VERSION 5.7 ;
  NOWIREEXTENSIONATPIN ON ;
  DIVIDERCHAR "/" ;
  BUSBITCHARS "[]" ;
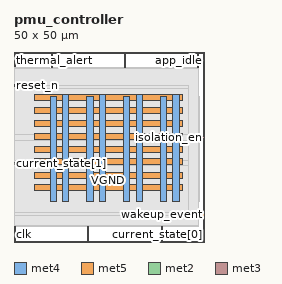
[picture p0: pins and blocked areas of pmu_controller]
MACRO pmu_controller
  CLASS BLOCK ;
  FOREIGN pmu_controller ;
  ORIGIN 0.000 0.000 ;
  SIZE 50.000 BY 50.000 ;
  PIN VGND
    DIRECTION INOUT ;
    USE GROUND ;
    PORT
      LAYER met4 ;
        RECT 12.850 10.640 14.450 38.760 ;
    END
    PORT
      LAYER met4 ;
        RECT 22.510 10.640 24.110 38.760 ;
    END
    PORT
      LAYER met4 ;
        RECT 32.170 10.640 33.770 38.760 ;
    END
    PORT
      LAYER met4 ;
        RECT 41.830 10.640 43.430 38.760 ;
    END
    PORT
      LAYER met5 ;
        RECT 5.280 16.775 44.400 18.375 ;
    END
    PORT
      LAYER met5 ;
        RECT 5.280 23.570 44.400 25.170 ;
    END
    PORT
      LAYER met5 ;
        RECT 5.280 30.365 44.400 31.965 ;
    END
    PORT
      LAYER met5 ;
        RECT 5.280 37.160 44.400 38.760 ;
    END
  END VGND
  PIN VPWR
    DIRECTION INOUT ;
    USE POWER ;
    PORT
      LAYER met4 ;
        RECT 9.550 10.640 11.150 38.320 ;
    END
    PORT
      LAYER met4 ;
        RECT 19.210 10.640 20.810 38.320 ;
    END
    PORT
      LAYER met4 ;
        RECT 28.870 10.640 30.470 38.320 ;
    END
    PORT
      LAYER met4 ;
        RECT 38.530 10.640 40.130 38.320 ;
    END
    PORT
      LAYER met5 ;
        RECT 5.280 13.475 44.400 15.075 ;
    END
    PORT
      LAYER met5 ;
        RECT 5.280 20.270 44.400 21.870 ;
    END
    PORT
      LAYER met5 ;
        RECT 5.280 27.065 44.400 28.665 ;
    END
    PORT
      LAYER met5 ;
        RECT 5.280 33.860 44.400 35.460 ;
    END
  END VPWR
  PIN app_idle
    DIRECTION INPUT ;
    USE SIGNAL ;
    ANTENNAGATEAREA 0.196500 ;
    PORT
      LAYER met2 ;
        RECT 48.390 46.000 48.670 50.000 ;
    END
  END app_idle
  PIN clk
    DIRECTION INPUT ;
    USE SIGNAL ;
    ANTENNAGATEAREA 0.852000 ;
    PORT
      LAYER met2 ;
        RECT 0.090 0.000 0.370 4.000 ;
    END
  END clk
  PIN clk_gate_en
    DIRECTION OUTPUT TRISTATE ;
    USE SIGNAL ;
    ANTENNADIFFAREA 0.795200 ;
    PORT
      LAYER met2 ;
        RECT 29.070 46.000 29.350 50.000 ;
    END
  END clk_gate_en
  PIN current_state[0]
    DIRECTION OUTPUT TRISTATE ;
    USE SIGNAL ;
    ANTENNADIFFAREA 0.795200 ;
    PORT
      LAYER met2 ;
        RECT 38.730 0.000 39.010 4.000 ;
    END
  END current_state[0]
  PIN current_state[1]
    DIRECTION OUTPUT TRISTATE ;
    USE SIGNAL ;
    ANTENNADIFFAREA 0.795200 ;
    PORT
      LAYER met3 ;
        RECT 0.000 20.440 4.000 21.040 ;
    END
  END current_state[1]
  PIN isolation_en
    DIRECTION OUTPUT TRISTATE ;
    USE SIGNAL ;
    ANTENNADIFFAREA 0.795200 ;
    PORT
      LAYER met3 ;
        RECT 46.000 27.240 50.000 27.840 ;
    END
  END isolation_en
  PIN pwr_gate_en
    DIRECTION OUTPUT TRISTATE ;
    USE SIGNAL ;
    ANTENNADIFFAREA 0.795200 ;
    PORT
      LAYER met2 ;
        RECT 19.410 0.000 19.690 4.000 ;
    END
  END pwr_gate_en
  PIN reset_n
    DIRECTION INPUT ;
    USE SIGNAL ;
    ANTENNAGATEAREA 0.196500 ;
    PORT
      LAYER met3 ;
        RECT 0.000 40.840 4.000 41.440 ;
    END
  END reset_n
  PIN thermal_alert
    DIRECTION INPUT ;
    USE SIGNAL ;
    ANTENNAGATEAREA 0.196500 ;
    PORT
      LAYER met2 ;
        RECT 9.750 46.000 10.030 50.000 ;
    END
  END thermal_alert
  PIN wakeup_event
    DIRECTION INPUT ;
    USE SIGNAL ;
    ANTENNAGATEAREA 0.196500 ;
    PORT
      LAYER met3 ;
        RECT 46.000 6.840 50.000 7.440 ;
    END
  END wakeup_event
  OBS
      LAYER li1 ;
        RECT 5.520 10.795 44.160 38.165 ;
      LAYER met1 ;
        RECT 4.670 10.640 48.690 38.320 ;
      LAYER met2 ;
        RECT 0.090 45.720 9.470 46.000 ;
        RECT 10.310 45.720 28.790 46.000 ;
        RECT 29.630 45.720 48.110 46.000 ;
        RECT 0.090 4.280 48.660 45.720 ;
        RECT 0.650 4.000 19.130 4.280 ;
        RECT 19.970 4.000 38.450 4.280 ;
        RECT 39.290 4.000 48.660 4.280 ;
      LAYER met3 ;
        RECT 4.400 40.440 46.000 41.305 ;
        RECT 0.065 28.240 46.000 40.440 ;
        RECT 0.065 26.840 45.600 28.240 ;
        RECT 0.065 21.440 46.000 26.840 ;
        RECT 4.400 20.040 46.000 21.440 ;
        RECT 0.065 7.840 46.000 20.040 ;
        RECT 0.065 6.975 45.600 7.840 ;
  END
END pmu_controller
END LIBRARY

